VERSION 5.7 ;
  NOWIREEXTENSIONATPIN ON ;
  DIVIDERCHAR "/" ;
  BUSBITCHARS "[]" ;
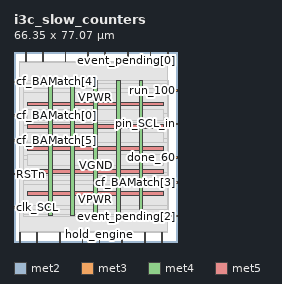
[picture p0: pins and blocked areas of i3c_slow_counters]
MACRO i3c_slow_counters
  CLASS BLOCK ;
  FOREIGN i3c_slow_counters ;
  ORIGIN 0.000 0.000 ;
  SIZE 66.350 BY 77.070 ;
  PIN CLK_SLOW
    DIRECTION INPUT ;
    USE SIGNAL ;
    PORT
      LAYER met2 ;
        RECT 9.290 0.000 9.570 4.000 ;
    END
  END CLK_SLOW
  PIN RSTn
    DIRECTION INPUT ;
    USE SIGNAL ;
    PORT
      LAYER met3 ;
        RECT 0.000 27.240 4.000 27.840 ;
    END
  END RSTn
  PIN cf_BAMatch[0]
    DIRECTION INPUT ;
    USE SIGNAL ;
    PORT
      LAYER met3 ;
        RECT 0.000 51.040 4.000 51.640 ;
    END
  END cf_BAMatch[0]
  PIN cf_BAMatch[1]
    DIRECTION INPUT ;
    USE SIGNAL ;
    PORT
      LAYER met2 ;
        RECT 4.690 73.070 4.970 77.070 ;
    END
  END cf_BAMatch[1]
  PIN cf_BAMatch[2]
    DIRECTION INPUT ;
    USE SIGNAL ;
    PORT
      LAYER met2 ;
        RECT 43.790 0.000 44.070 4.000 ;
    END
  END cf_BAMatch[2]
  PIN cf_BAMatch[3]
    DIRECTION INPUT ;
    USE SIGNAL ;
    PORT
      LAYER met3 ;
        RECT 62.350 23.840 66.350 24.440 ;
    END
  END cf_BAMatch[3]
  PIN cf_BAMatch[4]
    DIRECTION INPUT ;
    USE SIGNAL ;
    PORT
      LAYER met3 ;
        RECT 0.000 64.640 4.000 65.240 ;
    END
  END cf_BAMatch[4]
  PIN cf_BAMatch[5]
    DIRECTION INPUT ;
    USE SIGNAL ;
    PORT
      LAYER met3 ;
        RECT 0.000 40.840 4.000 41.440 ;
    END
  END cf_BAMatch[5]
  PIN cf_BAMatch[6]
    DIRECTION INPUT ;
    USE SIGNAL ;
    PORT
      LAYER met2 ;
        RECT 20.790 73.070 21.070 77.070 ;
    END
  END cf_BAMatch[6]
  PIN cf_BAMatch[7]
    DIRECTION INPUT ;
    USE SIGNAL ;
    PORT
      LAYER met2 ;
        RECT 11.590 73.070 11.870 77.070 ;
    END
  END cf_BAMatch[7]
  PIN cf_SlvEna
    DIRECTION INPUT ;
    USE SIGNAL ;
    PORT
      LAYER met2 ;
        RECT 62.190 73.070 62.470 77.070 ;
    END
  END cf_SlvEna
  PIN clk_SCL
    DIRECTION INPUT ;
    USE SIGNAL ;
    PORT
      LAYER met3 ;
        RECT 0.000 13.640 4.000 14.240 ;
    END
  END clk_SCL
  PIN clk_SCL_n
    DIRECTION INPUT ;
    USE SIGNAL ;
    PORT
      LAYER met2 ;
        RECT 18.490 0.000 18.770 4.000 ;
    END
  END clk_SCL_n
  PIN done_100
    DIRECTION OUTPUT TRISTATE ;
    USE SIGNAL ;
    PORT
      LAYER met2 ;
        RECT 27.690 0.000 27.970 4.000 ;
    END
  END done_100
  PIN done_60
    DIRECTION OUTPUT TRISTATE ;
    USE SIGNAL ;
    PORT
      LAYER met3 ;
        RECT 62.350 34.040 66.350 34.640 ;
    END
  END done_60
  PIN event_pending[0]
    DIRECTION INPUT ;
    USE SIGNAL ;
    PORT
      LAYER met2 ;
        RECT 46.090 73.070 46.370 77.070 ;
    END
  END event_pending[0]
  PIN event_pending[1]
    DIRECTION INPUT ;
    USE SIGNAL ;
    PORT
      LAYER met2 ;
        RECT 59.890 0.000 60.170 4.000 ;
    END
  END event_pending[1]
  PIN event_pending[2]
    DIRECTION INPUT ;
    USE SIGNAL ;
    PORT
      LAYER met3 ;
        RECT 62.350 10.240 66.350 10.840 ;
    END
  END event_pending[2]
  PIN force_sda
    DIRECTION OUTPUT TRISTATE ;
    USE SIGNAL ;
    PORT
      LAYER met2 ;
        RECT 55.290 73.070 55.570 77.070 ;
    END
  END force_sda
  PIN hold_engine
    DIRECTION OUTPUT TRISTATE ;
    USE SIGNAL ;
    PORT
      LAYER met2 ;
        RECT 34.590 0.000 34.870 4.000 ;
    END
  END hold_engine
  PIN int_in_STOP
    DIRECTION INPUT ;
    USE SIGNAL ;
    PORT
      LAYER met2 ;
        RECT 2.390 0.000 2.670 4.000 ;
    END
  END int_in_STOP
  PIN pin_SCL_in
    DIRECTION INPUT ;
    USE SIGNAL ;
    PORT
      LAYER met3 ;
        RECT 62.350 47.640 66.350 48.240 ;
    END
  END pin_SCL_in
  PIN pin_SDA_in
    DIRECTION INPUT ;
    USE SIGNAL ;
    PORT
      LAYER met2 ;
        RECT 36.890 73.070 37.170 77.070 ;
    END
  END pin_SDA_in
  PIN run_100
    DIRECTION INPUT ;
    USE SIGNAL ;
    PORT
      LAYER met3 ;
        RECT 62.350 61.240 66.350 61.840 ;
    END
  END run_100
  PIN run_60
    DIRECTION INPUT ;
    USE SIGNAL ;
    PORT
      LAYER met2 ;
        RECT 52.990 0.000 53.270 4.000 ;
    END
  END run_60
  PIN slow_gate
    DIRECTION OUTPUT TRISTATE ;
    USE SIGNAL ;
    PORT
      LAYER met2 ;
        RECT 29.990 73.070 30.270 77.070 ;
    END
  END slow_gate
  PIN VPWR
    DIRECTION INOUT ;
    USE POWER ;
    PORT
      LAYER met4 ;
        RECT 50.720 10.640 52.320 65.520 ;
    END
  END VPWR
  PIN VPWR
    DIRECTION INOUT ;
    USE POWER ;
    PORT
      LAYER met4 ;
        RECT 32.320 10.640 33.920 65.520 ;
    END
  END VPWR
  PIN VPWR
    DIRECTION INOUT ;
    USE POWER ;
    PORT
      LAYER met4 ;
        RECT 13.920 10.640 15.520 65.520 ;
    END
  END VPWR
  PIN VPWR
    DIRECTION INOUT ;
    USE POWER ;
    PORT
      LAYER met5 ;
        RECT 5.520 55.175 60.720 56.775 ;
    END
  END VPWR
  PIN VPWR
    DIRECTION INOUT ;
    USE POWER ;
    PORT
      LAYER met5 ;
        RECT 5.520 37.040 60.720 38.640 ;
    END
  END VPWR
  PIN VPWR
    DIRECTION INOUT ;
    USE POWER ;
    PORT
      LAYER met5 ;
        RECT 5.520 18.905 60.720 20.505 ;
    END
  END VPWR
  PIN VGND
    DIRECTION INOUT ;
    USE GROUND ;
    PORT
      LAYER met4 ;
        RECT 41.520 10.640 43.120 65.520 ;
    END
  END VGND
  PIN VGND
    DIRECTION INOUT ;
    USE GROUND ;
    PORT
      LAYER met4 ;
        RECT 23.120 10.640 24.720 65.520 ;
    END
  END VGND
  PIN VGND
    DIRECTION INOUT ;
    USE GROUND ;
    PORT
      LAYER met5 ;
        RECT 5.520 46.105 60.720 47.705 ;
    END
  END VGND
  PIN VGND
    DIRECTION INOUT ;
    USE GROUND ;
    PORT
      LAYER met5 ;
        RECT 5.520 27.975 60.720 29.575 ;
    END
  END VGND
  OBS
      LAYER li1 ;
        RECT 5.520 10.795 60.720 65.365 ;
      LAYER met1 ;
        RECT 2.370 10.640 62.490 65.520 ;
      LAYER met2 ;
        RECT 2.400 72.790 4.410 73.070 ;
        RECT 5.250 72.790 11.310 73.070 ;
        RECT 12.150 72.790 20.510 73.070 ;
        RECT 21.350 72.790 29.710 73.070 ;
        RECT 30.550 72.790 36.610 73.070 ;
        RECT 37.450 72.790 45.810 73.070 ;
        RECT 46.650 72.790 55.010 73.070 ;
        RECT 55.850 72.790 61.910 73.070 ;
        RECT 2.400 4.280 62.460 72.790 ;
        RECT 2.950 4.000 9.010 4.280 ;
        RECT 9.850 4.000 18.210 4.280 ;
        RECT 19.050 4.000 27.410 4.280 ;
        RECT 28.250 4.000 34.310 4.280 ;
        RECT 35.150 4.000 43.510 4.280 ;
        RECT 44.350 4.000 52.710 4.280 ;
        RECT 53.550 4.000 59.610 4.280 ;
        RECT 60.450 4.000 62.460 4.280 ;
      LAYER met3 ;
        RECT 4.400 64.240 62.350 65.445 ;
        RECT 4.000 62.240 62.350 64.240 ;
        RECT 4.000 60.840 61.950 62.240 ;
        RECT 4.000 52.040 62.350 60.840 ;
        RECT 4.400 50.640 62.350 52.040 ;
        RECT 4.000 48.640 62.350 50.640 ;
        RECT 4.000 47.240 61.950 48.640 ;
        RECT 4.000 41.840 62.350 47.240 ;
        RECT 4.400 40.440 62.350 41.840 ;
        RECT 4.000 35.040 62.350 40.440 ;
        RECT 4.000 33.640 61.950 35.040 ;
        RECT 4.000 28.240 62.350 33.640 ;
        RECT 4.400 26.840 62.350 28.240 ;
        RECT 4.000 24.840 62.350 26.840 ;
        RECT 4.000 23.440 61.950 24.840 ;
        RECT 4.000 14.640 62.350 23.440 ;
        RECT 4.400 13.240 62.350 14.640 ;
        RECT 4.000 11.240 62.350 13.240 ;
        RECT 4.000 10.375 61.950 11.240 ;
      LAYER met5 ;
        RECT 5.520 49.305 60.720 53.575 ;
        RECT 5.520 40.240 60.720 44.505 ;
        RECT 5.520 31.175 60.720 35.440 ;
  END
END i3c_slow_counters
END LIBRARY

